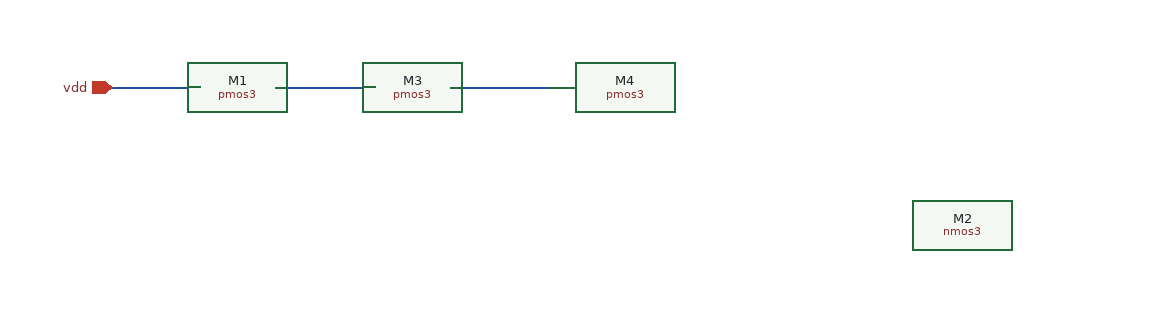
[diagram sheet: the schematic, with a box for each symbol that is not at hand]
v {xschem version=2.9.9 file_version=1.2 }
G {}
K {}
V {}
S {}
E {}
N -110 -30 -40 -30 { lab=vdd}
N 160 -30 240 -30 { lab=#net1}
N 20 -30 100 -30 { lab=#net2}
C {madvlsi/pmos3.sym} -10 -30 3 0 {name=M1
L=0.5
W=6
body=VDD
nf=1
mult=1
ad="'int((nf+1)/2) * W/nf * 0.29'" 
pd="'2*int((nf+1)/2) * (W/nf + 0.29)'"
as="'int((nf+2)/2) * W/nf * 0.29'" 
ps="'2*int((nf+2)/2) * (W/nf + 0.29)'"
nrd="'0.29 / W'" nrs="'0.29 / W'"
sa=0 sb=0 sd=0
model=pfet_01v8
spiceprefix=X
}
C {madvlsi/nmos3.sym} 570 80 0 0 {name=M2
L=0.5
W=6
body=GND
nf=1
mult=1
ad="'int((nf+1)/2) * W/nf * 0.29'" 
pd="'2*int((nf+1)/2) * (W/nf + 0.29)'"
as="'int((nf+2)/2) * W/nf * 0.29'" 
ps="'2*int((nf+2)/2) * (W/nf + 0.29)'"
nrd="'0.29 / W'" nrs="'0.29 / W'"
sa=0 sb=0 sd=0
model=nfet_01v8
spiceprefix=X
}
C {madvlsi/pmos3.sym} 130 -30 3 0 {name=M3
L=0.5
W=6
body=VDD
nf=1
mult=1
ad="'int((nf+1)/2) * W/nf * 0.29'" 
pd="'2*int((nf+1)/2) * (W/nf + 0.29)'"
as="'int((nf+2)/2) * W/nf * 0.29'" 
ps="'2*int((nf+2)/2) * (W/nf + 0.29)'"
nrd="'0.29 / W'" nrs="'0.29 / W'"
sa=0 sb=0 sd=0
model=pfet_01v8
spiceprefix=X
}
C {madvlsi/pmos3.sym} 270 -30 3 0 {name=M4
L=0.5
W=6
body=VDD
nf=1
mult=1
ad="'int((nf+1)/2) * W/nf * 0.29'" 
pd="'2*int((nf+1)/2) * (W/nf + 0.29)'"
as="'int((nf+2)/2) * W/nf * 0.29'" 
ps="'2*int((nf+2)/2) * (W/nf + 0.29)'"
nrd="'0.29 / W'" nrs="'0.29 / W'"
sa=0 sb=0 sd=0
model=pfet_01v8
spiceprefix=X
}
C {devices/iopin.sym} -110 -30 2 0 {name=p1 lab=vdd}
